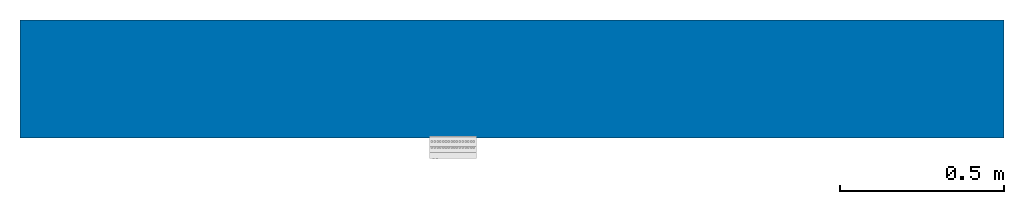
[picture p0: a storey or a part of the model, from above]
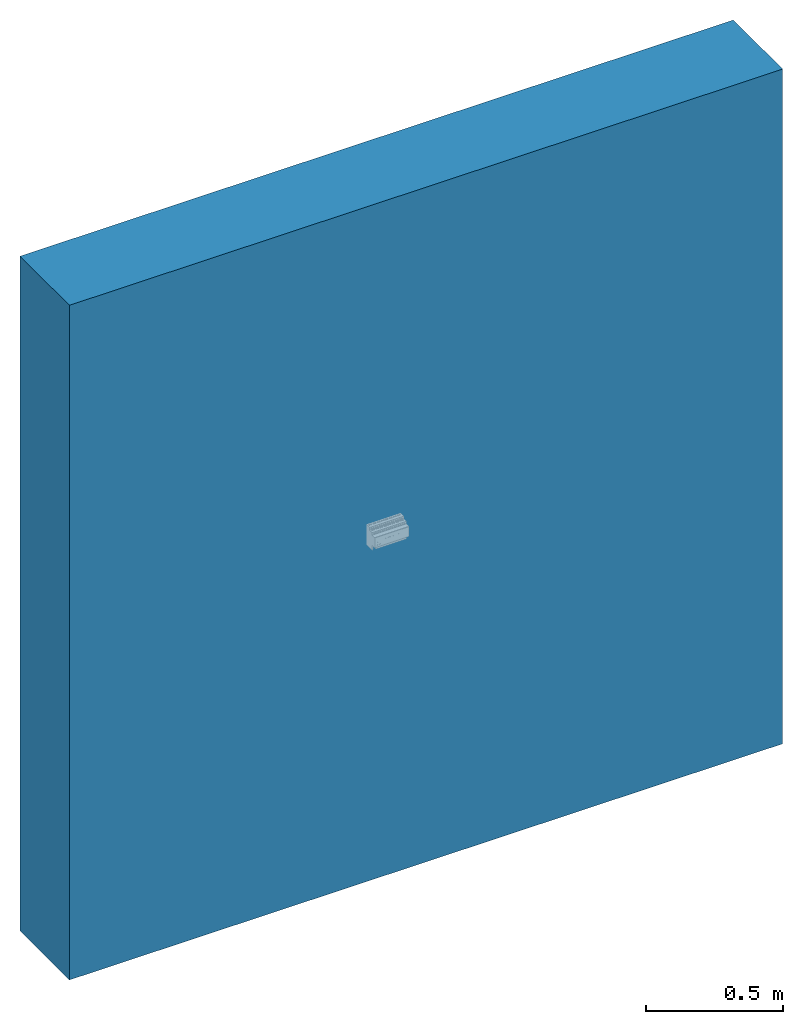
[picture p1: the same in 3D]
Properties of the parts of a building model (IFC2X3)

# File
Description: ViewDefinition [CoordinationView_V2.0]
File name: Projektnummer
Time: 2019-08-29T11:56:16
Written by: The EXPRESS Data Manager Version 5.02.0100.07 : 28 Aug 2013
Made in: 20160225_1515(x64) - Exporter 17.0.416.0 - Alternate UI 17.12.14.0
Comment: STEP Physical File produced by: The EXPRESS Data Manager Version 5.02.0100.07 : 28 Aug 2013 * Module: EDMstepFileFactory/EDMstandAlone * Creation date: Thu Aug 29 11:56:16 2019 * Host: B-BIM-NB-4736 * Database: C:\Users\Enkler\AppData\Local\Temp\{C00A4031-B6AC-4EC6-B7A5-DF184B08023E}\ifc * Database version: 5507 * Database creation date: Thu Aug 29 11:56:14 2019 * Schema: IFC2X3 * Model: DataRepository.ifc * Model creation date: Thu Aug 29 11:56:14 2019 * Header model: DataRepository.ifc_HeaderModel * Header model creation date: Thu Aug 29 11:56:14 2019 * EDMuser: sdai-user * EDMgroup: sdai-group * License ID and type: 5605 : Permanent license. Expiry date: * EDMstepFileFactory options: 020000

# IfcProject, Projektnummer
LongName: Projektname; Phase: Projektstatus

# IfcSite, Default
RefLatitude: 52, 30, 59, 765625; RefLongitude: 13, 23, 59, 998626; RefElevation: 0 m
Sonstige - Kategorie: Projektinformationen; Kundenname: Bauherr; Projektadresse: Projektadresse; Projektausgabedatum: Projekt Datum; Projektname: Projektname; Projektnummer: Projektnummer; Projektstatus: Projektstatus; Verfasser eMail: E-Mail; Verfasser Firma 1: Firma 1; Verfasser Firma 2: Firma 2; Verfasser PLZ Ort: PLZ Ort; Verfasser Strasse: Strasse; Verfasser Telefax: Telefax; Verfasser Telefon: Telefon

# IfcBuilding
Pset_BuildingCommon - NumberOfStoreys: 1
Sonstige - Kategorie: Projektinformationen; Kundenname: Bauherr; Projektadresse: Projektadresse; Projektausgabedatum: Projekt Datum; Projektname: Projektname; Projektnummer: Projektnummer; Projektstatus: Projektstatus; Verfasser eMail: E-Mail; Verfasser Firma 1: Firma 1; Verfasser Firma 2: Firma 2; Verfasser PLZ Ort: PLZ Ort; Verfasser Strasse: Strasse; Verfasser Telefax: Telefax; Verfasser Telefon: Telefon

# IfcBuildingStorey, Ebene 0
LongName: Ebene 0; Elevation: 0 m
Sonstige - Kategorie: Ebenen; Familienname: Ebene; Familie: Ebene: Ebene; Familie und Typ: Ebene: Ebene; Typ: Ebene: Ebene; Typ-ID: Ebene: Ebene
ID-Daten - Typname: Ebene; Tragwerk: no; Gebäudegeschoss: yes; Name: Ebene 0
Grafiken - Farbe: 16711680; Linienmuster: Verdeckt; Linienstärke: 1; Symbol: Beschriftung Ebene: Beschriftung Ebene; Symbol bei Ende 1 Standard: no; Symbol bei Ende 2 Standard: yes
Abhängigkeiten - Basishöhe: Projekt-Basispunkt; Ansicht: 0 m
Abmessungen - Höhe für Berechnung: 0 m

# IfcBuildingElementProxy: GIRA_100600_ENG, GIRA_100600_ENG:GIRA_100600_ENG:389849
In: Ebene 0
Type - Material: White
Type - Abhängigkeiten - Vorgabe-Ansicht: 1.2192 m
Type - Allgemein - Bus connection included YesNo: no; Bus system KNX radio YesNo: no; Bus system KNX YesNo: yes; Bus system LON YesNo: no; Bus system Powernet YesNo: no; Bus system radio frequent YesNo: no; Degree of protection (IP) Text: IP20; HeinzeBIM: https://www.heinze.de/bim/swit-act-8-g-16-a-man-act-knx-dra/d4fcfb5b85e485a27bd1f60f0d1efb30a04ed9a4; Local operation/hand operation: yes; Local operation/hand operation YesNo: yes; Mounting method Text: DRA (DIN-rail adapter); With LED indication: no
Type - Daten - Width in number of modular spacings: 8
Type - ID-Daten - Beschreibung: Swit.act.8g 16A DRA KNX,KNX switching actuator, 8-gang 16 A with manual actuation,,DRA plus,DRA switching actuators with integrated bus coupler. For switching independently controllable groups of loads. With manual switch for switching over the relay (On Off) parallel or without KNX operation. Multi-phase connection. No additional power supply required.,,Features:,- Manual actuation of the relay independent of the bus or switching position indication.,- NO contact or NC contact operation.,- Central switching function.,- Group feedback for reduction of bus load.,- Active or passive (object can be read out) cyclical feedback function.,- Feedback can be delayed until after the recovery of bus voltage.,- Logical linking function for each output.,- Block function can be parameterised for each channel. As an alternative, forced setting function for each output.,- Time functions (switch-on off delay, staircase light function – also with advance warning function).,- Integration in light scenes is possible, eight internal scenes at the most can be parameterised per channel.,- Memory function for light scenes.,- Elapsed operating time meter as forward backward counter with limit function (limit can be changed via bus) can be activated for each output.,- Input monitoring for cyclical updating with safety setting.,- Reactions in case of bus voltage failure and restoration can be set for each channel following an ETS programming process.,- Independent switching of the eight outputs.,,Notes :,- Installation on DIN top-hat rail.,- VDE approval in accordance with EN 60669-1, EN 60669-2-1.; GTIN: 4010337042181; HAN: 100600; Hersteller: Gira; Typname: GIRA_100600_ENG; URL: https://www.gira.de/
Type - Sonstige - Kategorie: Elektroinstallationen; Familienname: GIRA_100600_ENG
Pset_BuildingElementProxyCommon - Reference: GIRA_100600_ENG
Pset_ManufacturerTypeInformation - Manufacturer: Gira
Abhängigkeiten - Basisbauteil: Basiswand : MW 24.0 WD 12.0; Ebene: Ebene: Ebene 0; Erhebung: 1.54485 m
Abmessungen - Fläche: 0.029516 m2; Volumen: 0.000917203 m3
ID-Daten - Kennzeichen: 1
Phasen - Phase erstellt: Phase 1
Sonstige - Bauteillistenebene: Ebene: Ebene 0; Familie: GIRA_100600_ENG: GIRA_100600_ENG; Familie und Typ: GIRA_100600_ENG: GIRA_100600_ENG; Typ: GIRA_100600_ENG: GIRA_100600_ENG; Typ-ID: GIRA_100600_ENG: GIRA_100600_ENG

# IfcWallStandardCase: Basiswand:MW 24.0 WD 12.0, Basiswand:MW 24.0 WD 12.0:388663
In: Ebene 0
Type - PredefinedType: STANDARD; Material: Wärmedämmung - hart 0.12 m, Mauerwerk - Ziegel, verputzt 0.24 m
Type - Analytische Eigenschaften - Absorptionsgrad: 0.7; Rauigkeit: 3; Thermischer Widerstand (R): 3.87302; Thermisch wirksame Masse: 316537; Wärmeübergangskoeffizient (U): 0.258197
Type - Grafiken - Farbfüllung für groben Maßstab: 0; Füllmuster für groben Maßstab: Standard - Füllung
Type - ID-Daten - Beschreibung: Mauerwerk 24.0 cm, Wärmedämmung 12.0 cm; Typenkommentare: Mehrschaliges Mauerwerk; Typname: MW 24.0 WD 12.0
Type - Konstruktion - Abschluss an Öffnungen: Keine; Abschluss an Wänden: Keine; Breite: 0.36 m; Funktion: Außen
Type - Materialien und Oberflächen - Tragendes Material: Mauerwerk - Ziegel, verputzt
Type - Sonstige - Kategorie: Wände; Familienname: Basiswand
Abhängigkeiten - Abhängigkeit oben: Ebene: Ebene 1; Abhängigkeit unten: Ebene: Ebene 0; Basislinie: Wandachse; Für Körper: no; Nicht verknüpfte Höhe: 3 m; Oberkante ist fixiert.: no; Raumbegrenzung: yes; Unterkante ist fixiert: no; Verlängerungsabstand oben: 0 m; Verlängerungsabstand unten: 0 m; Versatz oben: 0 m; Versatz unten: 0 m
Abmessungen - Fläche: 9 m2; Länge: 3 m; Volumen: 3.24 m3
Phasen - Phase erstellt: Phase 1
Sonstige - Familie: Basiswand: MW 24.0 WD 12.0; Familie und Typ: Basiswand: MW 24.0 WD 12.0; Typ: Basiswand: MW 24.0 WD 12.0; Typ-ID: Basiswand: MW 24.0 WD 12.0
Tragwerk - Berechnungsmodell aktivieren: no; Tragwerk: no; Tragwerksverwendung: Nichttragend
Pset_WallCommon - Reference: MW 24.0 WD 12.0; LoadBearing: no; ExtendToStructure: no; IsExternal: yes; ThermalTransmittance: 0.258197 kg/K/s3
